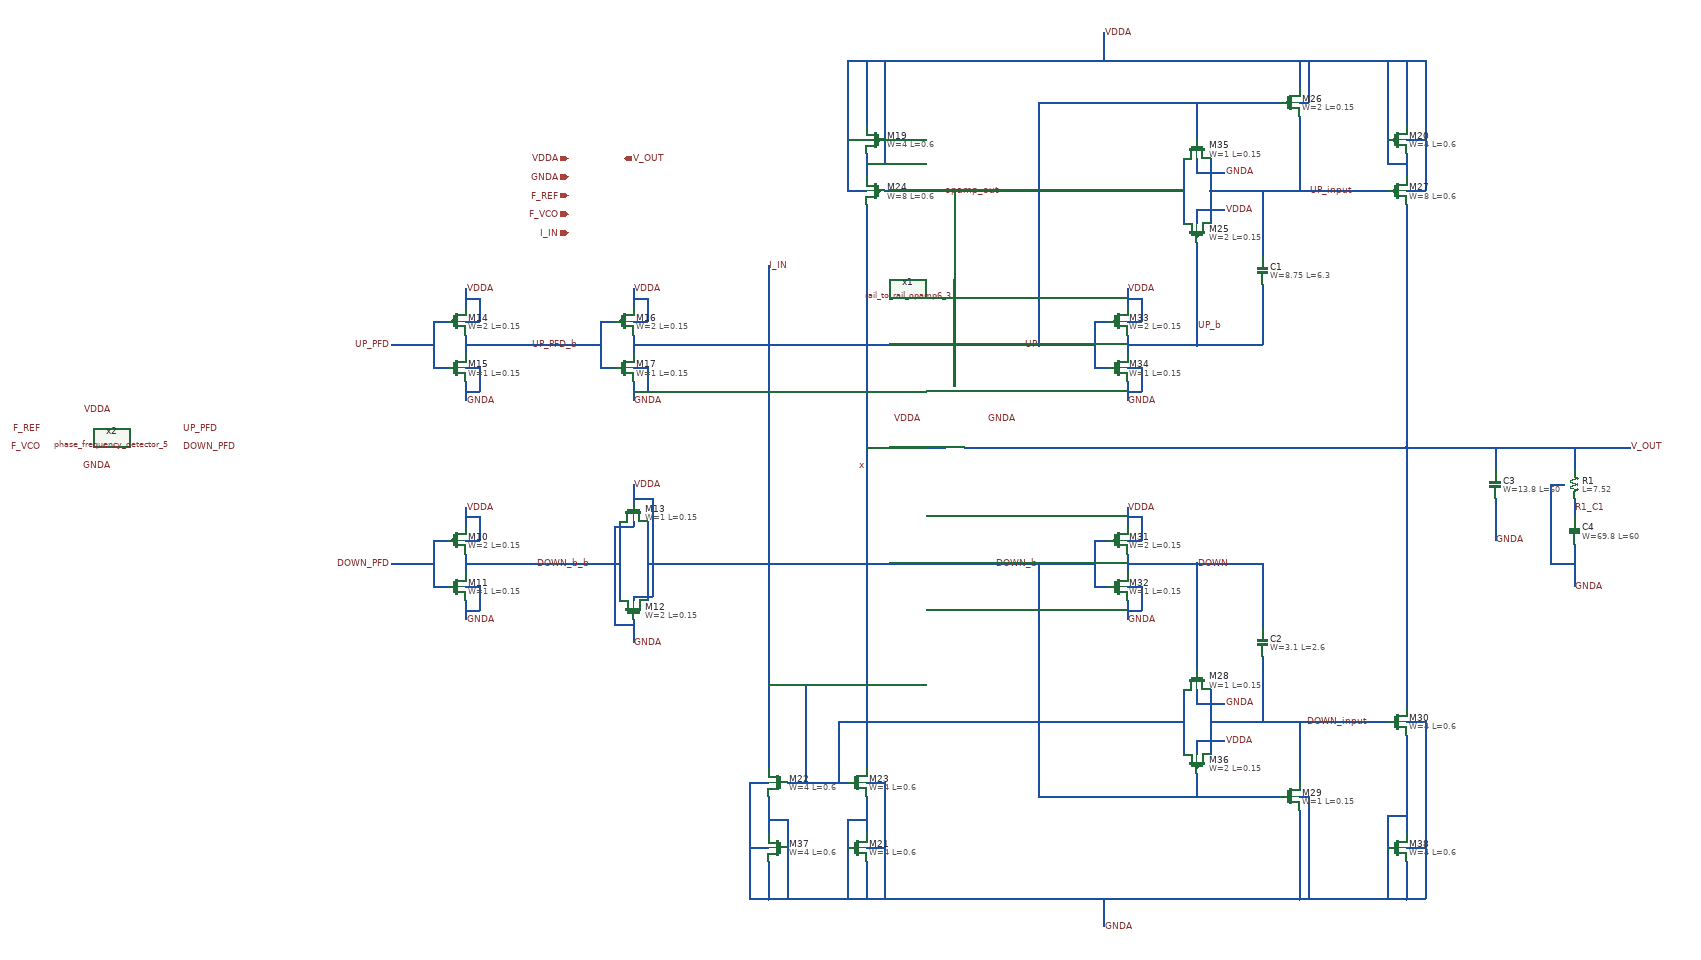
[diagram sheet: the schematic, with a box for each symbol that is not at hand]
v {xschem version=3.4.6 file_version=1.2}
G {}
K {}
V {}
S {}
E {}
N 1110 -1300 1210 -1300 {
lab=UP_PFD_b}
N 1150 -830 1340 -830 {
lab=DOWN_b_b}
N 850 -1300 890 -1300 {
lab=UP_PFD}
N 850 -830 890 -830 {
lab=DOWN_PFD}
N 1340 -920 1340 -750 {
lab=DOWN_b_b}
N 1400 -920 1400 -750 {
lab=DOWN_b}
N 1370 -1000 1370 -960 {
lab=VDDA}
N 1370 -760 1370 -750 {
lab=VDDA}
N 1370 -760 1410 -760 {
lab=VDDA}
N 1410 -970 1410 -760 {
lab=VDDA}
N 1370 -970 1410 -970 {
lab=VDDA}
N 1370 -920 1370 -910 {
lab=GNDA}
N 1330 -910 1370 -910 {
lab=GNDA}
N 1330 -910 1330 -700 {
lab=GNDA}
N 1330 -700 1370 -700 {
lab=GNDA}
N 1370 -710 1370 -660 {
lab=GNDA}
N 1010 -850 1010 -810 {
lab=DOWN_b_b}
N 940 -880 970 -880 {
lab=DOWN_PFD}
N 940 -880 940 -780 {
lab=DOWN_PFD}
N 940 -780 970 -780 {
lab=DOWN_PFD}
N 1010 -830 1150 -830 {
lab=DOWN_b_b}
N 890 -830 940 -830 {
lab=DOWN_PFD}
N 1010 -750 1010 -710 {
lab=GNDA}
N 1010 -950 1010 -910 {
lab=VDDA}
N 1010 -880 1040 -880 {
lab=VDDA}
N 1040 -930 1040 -880 {
lab=VDDA}
N 1010 -930 1040 -930 {
lab=VDDA}
N 1010 -780 1040 -780 {
lab=GNDA}
N 1040 -780 1040 -730 {
lab=GNDA}
N 1010 -730 1040 -730 {
lab=GNDA}
N 1010 -1320 1010 -1280 {
lab=UP_PFD_b}
N 940 -1350 970 -1350 {
lab=UP_PFD}
N 940 -1350 940 -1250 {
lab=UP_PFD}
N 940 -1250 970 -1250 {
lab=UP_PFD}
N 1010 -1300 1110 -1300 {
lab=UP_PFD_b}
N 890 -1300 940 -1300 {
lab=UP_PFD}
N 1010 -1220 1010 -1180 {
lab=GNDA}
N 1010 -1420 1010 -1380 {
lab=VDDA}
N 1010 -1350 1040 -1350 {
lab=VDDA}
N 1040 -1400 1040 -1350 {
lab=VDDA}
N 1010 -1400 1040 -1400 {
lab=VDDA}
N 1010 -1250 1040 -1250 {
lab=GNDA}
N 1040 -1250 1040 -1200 {
lab=GNDA}
N 1010 -1200 1040 -1200 {
lab=GNDA}
N 1370 -1320 1370 -1280 {
lab=UP}
N 1300 -1350 1330 -1350 {
lab=UP_PFD_b}
N 1300 -1350 1300 -1250 {
lab=UP_PFD_b}
N 1300 -1250 1330 -1250 {
lab=UP_PFD_b}
N 1210 -1300 1300 -1300 {
lab=UP_PFD_b}
N 1370 -1220 1370 -1180 {
lab=GNDA}
N 1370 -1420 1370 -1380 {
lab=VDDA}
N 1370 -1350 1400 -1350 {
lab=VDDA}
N 1400 -1400 1400 -1350 {
lab=VDDA}
N 1370 -1400 1400 -1400 {
lab=VDDA}
N 1370 -1250 1400 -1250 {
lab=GNDA}
N 1400 -1250 1400 -1200 {
lab=GNDA}
N 1370 -1200 1400 -1200 {
lab=GNDA}
N 1370 -1300 2240 -1300 {
lab=UP}
N 1700 -360 1830 -360 {
lab=I_IN}
N 1660 -110 2160 -110 {
lab=GNDA}
N 1620 -360 1660 -360 {
lab=GNDA}
N 1620 -360 1620 -110 {
lab=GNDA}
N 1620 -110 1660 -110 {
lab=GNDA}
N 1870 -360 1910 -360 {
lab=GNDA}
N 1830 -1630 1870 -1630 {
lab=VDDA}
N 2160 -110 2200 -110 {
lab=GNDA}
N 1830 -1910 1830 -1630 {
lab=VDDA}
N 2800 -1910 2800 -1850 {
lab=VDDA}
N 2800 -1820 2820 -1820 {
lab=VDDA}
N 2820 -1910 2820 -1820 {
lab=VDDA}
N 3070 -1910 3070 -1630 {
lab=VDDA}
N 2200 -110 2800 -110 {
lab=GNDA}
N 2800 -300 2800 -110 {
lab=GNDA}
N 3030 -490 3070 -490 {
lab=GNDA}
N 3030 -110 3070 -110 {
lab=GNDA}
N 2060 -1630 2060 -1210 {
lab=opamp_out}
N 1740 -570 1740 -360 {
lab=I_IN}
N 1660 -570 1740 -570 {
lab=I_IN}
N 1910 -360 1910 -110 {
lab=GNDA}
N 1810 -490 2550 -490 {
lab=I_IN}
N 2580 -1520 2580 -1300 {
lab=UP_b}
N 2240 -1820 2760 -1820 {
lab=UP}
N 2240 -1820 2240 -1300 {
lab=UP}
N 2800 -1790 2800 -1630 {
lab=UP_input}
N 2610 -1630 2990 -1630 {
lab=UP_input}
N 2520 -830 2580 -830 {
lab=DOWN}
N 2580 -830 2580 -600 {
lab=DOWN}
N 2240 -830 2240 -330 {
lab=DOWN_b}
N 2240 -330 2760 -330 {
lab=DOWN_b}
N 2430 -850 2430 -810 {
lab=DOWN}
N 2360 -880 2390 -880 {
lab=DOWN_b}
N 2360 -880 2360 -780 {
lab=DOWN_b}
N 2360 -780 2390 -780 {
lab=DOWN_b}
N 2430 -750 2430 -710 {
lab=GNDA}
N 2430 -950 2430 -910 {
lab=VDDA}
N 2430 -880 2460 -880 {
lab=VDDA}
N 2460 -930 2460 -880 {
lab=VDDA}
N 2430 -930 2460 -930 {
lab=VDDA}
N 2430 -780 2460 -780 {
lab=GNDA}
N 2460 -780 2460 -730 {
lab=GNDA}
N 2430 -730 2460 -730 {
lab=GNDA}
N 2430 -830 2520 -830 {
lab=DOWN}
N 2430 -1320 2430 -1280 {
lab=UP_b}
N 2360 -1350 2390 -1350 {
lab=UP}
N 2360 -1350 2360 -1250 {
lab=UP}
N 2360 -1250 2390 -1250 {
lab=UP}
N 2240 -1300 2360 -1300 {
lab=UP}
N 2430 -1220 2430 -1180 {
lab=GNDA}
N 2430 -1420 2430 -1380 {
lab=VDDA}
N 2430 -1350 2460 -1350 {
lab=VDDA}
N 2460 -1400 2460 -1350 {
lab=VDDA}
N 2430 -1400 2460 -1400 {
lab=VDDA}
N 2430 -1250 2460 -1250 {
lab=GNDA}
N 2460 -1250 2460 -1200 {
lab=GNDA}
N 2430 -1200 2460 -1200 {
lab=GNDA}
N 2430 -1300 2520 -1300 {
lab=UP_b}
N 2520 -1300 2580 -1300 {
lab=UP_b}
N 1660 -610 1660 -390 {
lab=I_IN}
N 1660 -670 1660 -610 {
lab=I_IN}
N 2610 -1700 2610 -1630 {
lab=UP_input}
N 2550 -1700 2550 -1560 {
lab=opamp_out}
N 2610 -1630 2610 -1560 {
lab=UP_input}
N 1910 -1630 2550 -1630 {
lab=opamp_out}
N 2800 -110 3030 -110 {
lab=GNDA}
N 2610 -560 2610 -420 {
lab=DOWN_input}
N 2550 -560 2550 -420 {
lab=I_IN}
N 2610 -490 2990 -490 {
lab=DOWN_input}
N 3070 -490 3070 -110 {
lab=GNDA}
N 1810 -490 1810 -360 {
lab=I_IN}
N 2800 -490 2800 -360 {
lab=DOWN_input}
N 2800 -330 2820 -330 {
lab=GNDA}
N 2820 -330 2820 -110 {
lab=GNDA}
N 2580 -380 2580 -330 {
lab=DOWN_b}
N 2580 -1820 2580 -1740 {
lab=UP}
N 2580 -1300 2720 -1300 {
lab=UP_b}
N 2720 -1430 2720 -1300 {
lab=UP_b}
N 2720 -1630 2720 -1490 {
lab=UP_input}
N 2720 -830 2720 -690 {
lab=DOWN}
N 2720 -630 2720 -490 {
lab=DOWN_input}
N 2580 -830 2720 -830 {
lab=DOWN}
N 3030 -1080 3110 -1080 {
lab=V_OUT}
N 1400 -830 2240 -830 {
lab=DOWN_b}
N 2240 -830 2360 -830 {
lab=DOWN_b}
N 2380 -1970 2380 -1910 {
lab=VDDA}
N 2380 -110 2380 -50 {
lab=GNDA}
N 2580 -450 2640 -450 {
lab=VDDA}
N 2580 -450 2580 -420 {
lab=VDDA}
N 2580 -560 2580 -530 {
lab=GNDA}
N 2580 -530 2640 -530 {
lab=GNDA}
N 2580 -1590 2640 -1590 {
lab=VDDA}
N 2580 -1590 2580 -1560 {
lab=VDDA}
N 2580 -1700 2580 -1670 {
lab=GNDA}
N 2580 -1670 2640 -1670 {
lab=GNDA}
N 1660 -1470 1660 -670 {lab=I_IN}
N 1870 -1600 1870 -390 {lab=x}
N 3030 -1600 3030 -1080 {lab=V_OUT}
N 3030 -1080 3030 -520 {lab=V_OUT}
N 1870 -1080 2040 -1080 {lab=x}
N 2080 -1080 3030 -1080 {lab=V_OUT}
N 1830 -1740 1870 -1740 {
lab=VDDA}
N 1870 -1710 1870 -1660 {lab=VDDA}
N 1870 -1910 1870 -1770 {lab=VDDA}
N 3030 -1710 3030 -1660 {lab=VDDA}
N 3030 -1910 3030 -1770 {lab=VDDA}
N 2990 -1910 2990 -1740 {lab=VDDA}
N 1910 -1910 1910 -1740 {lab=VDDA}
N 1870 -1690 1910 -1690 {lab=VDDA}
N 1910 -1740 1910 -1690 {lab=VDDA}
N 3030 -1740 3070 -1740 {lab=VDDA}
N 2990 -1690 3030 -1690 {lab=VDDA}
N 2990 -1740 2990 -1690 {lab=VDDA}
N 3030 -1630 3070 -1630 {lab=VDDA}
N 1660 -330 1660 -250 {
lab=GNDA}
N 1870 -330 1870 -250 {
lab=GNDA}
N 3030 -460 3030 -250 {
lab=GNDA}
N 1620 -220 1660 -220 {
lab=GNDA}
N 1870 -220 1910 -220 {
lab=GNDA}
N 1660 -190 1660 -110 {lab=GNDA}
N 1870 -190 1870 -110 {lab=GNDA}
N 1830 -220 1830 -110 {lab=GNDA}
N 1700 -220 1700 -110 {lab=GNDA}
N 1660 -280 1700 -280 {lab=GNDA}
N 1700 -280 1700 -220 {lab=GNDA}
N 1830 -280 1830 -220 {lab=GNDA}
N 1830 -280 1870 -280 {lab=GNDA}
N 3030 -190 3030 -110 {lab=GNDA}
N 2990 -220 2990 -110 {lab=GNDA}
N 2990 -290 2990 -220 {lab=GNDA}
N 2990 -290 3030 -290 {lab=GNDA}
N 3030 -220 3070 -220 {lab=GNDA}
N 1830 -1910 3070 -1910 {lab=VDDA}
N 3390 -970 3390 -920 {
lab=R1_C1}
N 3340 -1000 3370 -1000 {
lab=GNDA}
N 3340 -1000 3340 -830 {
lab=GNDA}
N 3340 -830 3390 -830 {
lab=GNDA}
N 3390 -870 3390 -780 {lab=GNDA}
N 3110 -1080 3510 -1080 {lab=V_OUT}
N 3220 -1080 3220 -1030 {lab=V_OUT}
N 3390 -1080 3390 -1030 {lab=V_OUT}
N 3220 -970 3220 -880 {lab=GNDA}
C {devices/lab_wire.sym} 1150 -1300 0 1 {name=p15 sig_type=std_logic lab=UP_PFD_b}
C {devices/lab_wire.sym} 850 -1300 0 0 {name=p2 sig_type=std_logic lab=UP_PFD}
C {devices/lab_wire.sym} 850 -830 2 1 {name=p7 sig_type=std_logic lab=DOWN_PFD}
C {sky130_fd_pr/pfet_01v8.sym} 1370 -730 3 0 {name=M12
L=0.15
W=2
nf=2
mult=1
ad="'int((nf+1)/2) * W/nf * 0.29'" 
pd="'2*int((nf+1)/2) * (W/nf + 0.29)'"
as="'int((nf+2)/2) * W/nf * 0.29'" 
ps="'2*int((nf+2)/2) * (W/nf + 0.29)'"
nrd="'0.29 / W'" nrs="'0.29 / W'"
sa=0 sb=0 sd=0
model=pfet_01v8
spiceprefix=X
}
C {sky130_fd_pr/nfet_01v8.sym} 1370 -940 1 0 {name=M13
L=0.15
W=1
nf=1 
mult=1
ad="'int((nf+1)/2) * W/nf * 0.29'" 
pd="'2*int((nf+1)/2) * (W/nf + 0.29)'"
as="'int((nf+2)/2) * W/nf * 0.29'" 
ps="'2*int((nf+2)/2) * (W/nf + 0.29)'"
nrd="'0.29 / W'" nrs="'0.29 / W'"
sa=0 sb=0 sd=0
model=nfet_01v8
spiceprefix=X
}
C {sky130_fd_pr/pfet_01v8.sym} 990 -880 0 0 {name=M10
L=0.15
W=2
nf=2
mult=1
ad="'int((nf+1)/2) * W/nf * 0.29'" 
pd="'2*int((nf+1)/2) * (W/nf + 0.29)'"
as="'int((nf+2)/2) * W/nf * 0.29'" 
ps="'2*int((nf+2)/2) * (W/nf + 0.29)'"
nrd="'0.29 / W'" nrs="'0.29 / W'"
sa=0 sb=0 sd=0
model=pfet_01v8
spiceprefix=X
}
C {sky130_fd_pr/nfet_01v8.sym} 990 -780 2 1 {name=M11
L=0.15
W=1
nf=1 
mult=1
ad="'int((nf+1)/2) * W/nf * 0.29'" 
pd="'2*int((nf+1)/2) * (W/nf + 0.29)'"
as="'int((nf+2)/2) * W/nf * 0.29'" 
ps="'2*int((nf+2)/2) * (W/nf + 0.29)'"
nrd="'0.29 / W'" nrs="'0.29 / W'"
sa=0 sb=0 sd=0
model=nfet_01v8
spiceprefix=X
}
C {sky130_fd_pr/pfet_01v8.sym} 990 -1350 0 0 {name=M14
L=0.15
W=2
nf=2
mult=1
ad="'int((nf+1)/2) * W/nf * 0.29'" 
pd="'2*int((nf+1)/2) * (W/nf + 0.29)'"
as="'int((nf+2)/2) * W/nf * 0.29'" 
ps="'2*int((nf+2)/2) * (W/nf + 0.29)'"
nrd="'0.29 / W'" nrs="'0.29 / W'"
sa=0 sb=0 sd=0
model=pfet_01v8
spiceprefix=X
}
C {sky130_fd_pr/nfet_01v8.sym} 990 -1250 2 1 {name=M15
L=0.15
W=1
nf=1 
mult=1
ad="'int((nf+1)/2) * W/nf * 0.29'" 
pd="'2*int((nf+1)/2) * (W/nf + 0.29)'"
as="'int((nf+2)/2) * W/nf * 0.29'" 
ps="'2*int((nf+2)/2) * (W/nf + 0.29)'"
nrd="'0.29 / W'" nrs="'0.29 / W'"
sa=0 sb=0 sd=0
model=nfet_01v8
spiceprefix=X
}
C {sky130_fd_pr/pfet_01v8.sym} 1350 -1350 0 0 {name=M16
L=0.15
W=2
nf=2
mult=1
ad="'int((nf+1)/2) * W/nf * 0.29'" 
pd="'2*int((nf+1)/2) * (W/nf + 0.29)'"
as="'int((nf+2)/2) * W/nf * 0.29'" 
ps="'2*int((nf+2)/2) * (W/nf + 0.29)'"
nrd="'0.29 / W'" nrs="'0.29 / W'"
sa=0 sb=0 sd=0
model=pfet_01v8
spiceprefix=X
}
C {sky130_fd_pr/nfet_01v8.sym} 1350 -1250 2 1 {name=M17
L=0.15
W=1
nf=1 
mult=1
ad="'int((nf+1)/2) * W/nf * 0.29'" 
pd="'2*int((nf+1)/2) * (W/nf + 0.29)'"
as="'int((nf+2)/2) * W/nf * 0.29'" 
ps="'2*int((nf+2)/2) * (W/nf + 0.29)'"
nrd="'0.29 / W'" nrs="'0.29 / W'"
sa=0 sb=0 sd=0
model=nfet_01v8
spiceprefix=X
}
C {devices/ipin.sym} 1230 -1700 0 0 {name=p3 lab=VDDA}
C {devices/opin.sym} 1350 -1700 0 0 {name=p11 lab=V_OUT}
C {devices/lab_pin.sym} 1010 -710 0 1 {name=p27 sig_type=std_logic lab=GNDA}
C {devices/lab_pin.sym} 1010 -950 0 1 {name=p28 sig_type=std_logic lab=VDDA}
C {devices/lab_pin.sym} 1370 -660 0 1 {name=p29 sig_type=std_logic lab=GNDA}
C {devices/lab_pin.sym} 1370 -1000 0 1 {name=p30 sig_type=std_logic lab=VDDA}
C {devices/lab_pin.sym} 1010 -1180 0 1 {name=p31 sig_type=std_logic lab=GNDA}
C {devices/lab_pin.sym} 1010 -1420 0 1 {name=p32 sig_type=std_logic lab=VDDA}
C {devices/lab_pin.sym} 1370 -1180 0 1 {name=p33 sig_type=std_logic lab=GNDA}
C {devices/lab_pin.sym} 1370 -1420 0 1 {name=p34 sig_type=std_logic lab=VDDA}
C {devices/ipin.sym} 1230 -1660 0 0 {name=p35 lab=GNDA}
C {devices/ipin.sym} 1230 -1620 0 0 {name=p36 lab=F_REF}
C {devices/ipin.sym} 1230 -1580 0 0 {name=p37 lab=F_VCO}
C {devices/ipin.sym} 1230 -1540 0 0 {name=p38 lab=I_IN}
C {sky130_fd_pr/nfet_01v8.sym} 1680 -360 0 1 {name=M22
L=0.6
W=4
nf=2 
mult=1
ad="'int((nf+1)/2) * W/nf * 0.29'" 
pd="'2*int((nf+1)/2) * (W/nf + 0.29)'"
as="'int((nf+2)/2) * W/nf * 0.29'" 
ps="'2*int((nf+2)/2) * (W/nf + 0.29)'"
nrd="'0.29 / W'" nrs="'0.29 / W'"
sa=0 sb=0 sd=0
model=nfet_01v8
spiceprefix=X
}
C {sky130_fd_pr/nfet_01v8.sym} 1850 -360 0 0 {name=M23
L=0.6
W=4
nf=2 
mult=1
ad="'int((nf+1)/2) * W/nf * 0.29'" 
pd="'2*int((nf+1)/2) * (W/nf + 0.29)'"
as="'int((nf+2)/2) * W/nf * 0.29'" 
ps="'2*int((nf+2)/2) * (W/nf + 0.29)'"
nrd="'0.29 / W'" nrs="'0.29 / W'"
sa=0 sb=0 sd=0
model=nfet_01v8
spiceprefix=X
}
C {sky130_fd_pr/pfet_01v8.sym} 1890 -1630 2 0 {name=M24
L=0.6
W=8
nf=4
mult=1
ad="'int((nf+1)/2) * W/nf * 0.29'" 
pd="'2*int((nf+1)/2) * (W/nf + 0.29)'"
as="'int((nf+2)/2) * W/nf * 0.29'" 
ps="'2*int((nf+2)/2) * (W/nf + 0.29)'"
nrd="'0.29 / W'" nrs="'0.29 / W'"
sa=0 sb=0 sd=0
model=pfet_01v8
spiceprefix=X
}
C {devices/lab_wire.sym} 1870 -1040 0 0 {name=p9 sig_type=std_logic lab=x}
C {sky130_fd_pr/pfet_01v8.sym} 2580 -1540 3 0 {name=M25
L=0.15
W=2
nf=2
mult=1
ad="'int((nf+1)/2) * W/nf * 0.29'" 
pd="'2*int((nf+1)/2) * (W/nf + 0.29)'"
as="'int((nf+2)/2) * W/nf * 0.29'" 
ps="'2*int((nf+2)/2) * (W/nf + 0.29)'"
nrd="'0.29 / W'" nrs="'0.29 / W'"
sa=0 sb=0 sd=0
model=pfet_01v8
spiceprefix=X
}
C {sky130_fd_pr/pfet_01v8.sym} 2780 -1820 0 0 {name=M26
L=0.15
W=2
nf=2
mult=1
ad="'int((nf+1)/2) * W/nf * 0.29'" 
pd="'2*int((nf+1)/2) * (W/nf + 0.29)'"
as="'int((nf+2)/2) * W/nf * 0.29'" 
ps="'2*int((nf+2)/2) * (W/nf + 0.29)'"
nrd="'0.29 / W'" nrs="'0.29 / W'"
sa=0 sb=0 sd=0
model=pfet_01v8
spiceprefix=X
}
C {sky130_fd_pr/pfet_01v8.sym} 3010 -1630 0 0 {name=M27
L=0.6
W=8
nf=4
mult=1
ad="'int((nf+1)/2) * W/nf * 0.29'" 
pd="'2*int((nf+1)/2) * (W/nf + 0.29)'"
as="'int((nf+2)/2) * W/nf * 0.29'" 
ps="'2*int((nf+2)/2) * (W/nf + 0.29)'"
nrd="'0.29 / W'" nrs="'0.29 / W'"
sa=0 sb=0 sd=0
model=pfet_01v8
spiceprefix=X
}
C {devices/lab_wire.sym} 2240 -1300 2 1 {name=p19 sig_type=std_logic lab=UP}
C {devices/lab_wire.sym} 2580 -1340 0 1 {name=p39 sig_type=std_logic lab=UP_b}
C {sky130_fd_pr/nfet_01v8.sym} 2580 -580 1 0 {name=M28
L=0.15
W=1
nf=1 
mult=1
ad="'int((nf+1)/2) * W/nf * 0.29'" 
pd="'2*int((nf+1)/2) * (W/nf + 0.29)'"
as="'int((nf+2)/2) * W/nf * 0.29'" 
ps="'2*int((nf+2)/2) * (W/nf + 0.29)'"
nrd="'0.29 / W'" nrs="'0.29 / W'"
sa=0 sb=0 sd=0
model=nfet_01v8
spiceprefix=X
}
C {sky130_fd_pr/nfet_01v8.sym} 2780 -330 0 0 {name=M29
L=0.15
W=1
nf=1 
mult=1
ad="'int((nf+1)/2) * W/nf * 0.29'" 
pd="'2*int((nf+1)/2) * (W/nf + 0.29)'"
as="'int((nf+2)/2) * W/nf * 0.29'" 
ps="'2*int((nf+2)/2) * (W/nf + 0.29)'"
nrd="'0.29 / W'" nrs="'0.29 / W'"
sa=0 sb=0 sd=0
model=nfet_01v8
spiceprefix=X
}
C {devices/lab_wire.sym} 2240 -830 0 0 {name=p40 sig_type=std_logic lab=DOWN_b}
C {sky130_fd_pr/nfet_01v8.sym} 3010 -490 0 0 {name=M30
L=0.6
W=4
nf=2 
mult=1
ad="'int((nf+1)/2) * W/nf * 0.29'" 
pd="'2*int((nf+1)/2) * (W/nf + 0.29)'"
as="'int((nf+2)/2) * W/nf * 0.29'" 
ps="'2*int((nf+2)/2) * (W/nf + 0.29)'"
nrd="'0.29 / W'" nrs="'0.29 / W'"
sa=0 sb=0 sd=0
model=nfet_01v8
spiceprefix=X
}
C {devices/lab_wire.sym} 2820 -1630 2 0 {name=p41 sig_type=std_logic lab=UP_input}
C {devices/lab_wire.sym} 2950 -490 0 0 {name=p42 sig_type=std_logic lab=DOWN_input}
C {devices/lab_wire.sym} 2160 -1630 0 0 {name=p43 sig_type=std_logic lab=opamp_out}
C {sky130_fd_pr/pfet_01v8.sym} 2410 -880 0 0 {name=M31
L=0.15
W=2
nf=2
mult=1
ad="'int((nf+1)/2) * W/nf * 0.29'" 
pd="'2*int((nf+1)/2) * (W/nf + 0.29)'"
as="'int((nf+2)/2) * W/nf * 0.29'" 
ps="'2*int((nf+2)/2) * (W/nf + 0.29)'"
nrd="'0.29 / W'" nrs="'0.29 / W'"
sa=0 sb=0 sd=0
model=pfet_01v8
spiceprefix=X
}
C {sky130_fd_pr/nfet_01v8.sym} 2410 -780 2 1 {name=M32
L=0.15
W=1
nf=1 
mult=1
ad="'int((nf+1)/2) * W/nf * 0.29'" 
pd="'2*int((nf+1)/2) * (W/nf + 0.29)'"
as="'int((nf+2)/2) * W/nf * 0.29'" 
ps="'2*int((nf+2)/2) * (W/nf + 0.29)'"
nrd="'0.29 / W'" nrs="'0.29 / W'"
sa=0 sb=0 sd=0
model=nfet_01v8
spiceprefix=X
}
C {sky130_fd_pr/pfet_01v8.sym} 2410 -1350 0 0 {name=M33
L=0.15
W=2
nf=2
mult=1
ad="'int((nf+1)/2) * W/nf * 0.29'" 
pd="'2*int((nf+1)/2) * (W/nf + 0.29)'"
as="'int((nf+2)/2) * W/nf * 0.29'" 
ps="'2*int((nf+2)/2) * (W/nf + 0.29)'"
nrd="'0.29 / W'" nrs="'0.29 / W'"
sa=0 sb=0 sd=0
model=pfet_01v8
spiceprefix=X
}
C {sky130_fd_pr/nfet_01v8.sym} 2410 -1250 2 1 {name=M34
L=0.15
W=1
nf=1 
mult=1
ad="'int((nf+1)/2) * W/nf * 0.29'" 
pd="'2*int((nf+1)/2) * (W/nf + 0.29)'"
as="'int((nf+2)/2) * W/nf * 0.29'" 
ps="'2*int((nf+2)/2) * (W/nf + 0.29)'"
nrd="'0.29 / W'" nrs="'0.29 / W'"
sa=0 sb=0 sd=0
model=nfet_01v8
spiceprefix=X
}
C {devices/lab_wire.sym} 1660 -1470 0 1 {name=p44 sig_type=std_logic lab=I_IN}
C {devices/lab_wire.sym} 2580 -830 0 1 {name=p45 sig_type=std_logic lab=DOWN}
C {sky130_fd_pr/nfet_01v8.sym} 2580 -1720 1 0 {name=M35
L=0.15
W=1
nf=1 
mult=1
ad="'int((nf+1)/2) * W/nf * 0.29'" 
pd="'2*int((nf+1)/2) * (W/nf + 0.29)'"
as="'int((nf+2)/2) * W/nf * 0.29'" 
ps="'2*int((nf+2)/2) * (W/nf + 0.29)'"
nrd="'0.29 / W'" nrs="'0.29 / W'"
sa=0 sb=0 sd=0
model=nfet_01v8
spiceprefix=X
}
C {sky130_fd_pr/pfet_01v8.sym} 2580 -400 3 0 {name=M36
L=0.15
W=2
nf=2
mult=1
ad="'int((nf+1)/2) * W/nf * 0.29'" 
pd="'2*int((nf+1)/2) * (W/nf + 0.29)'"
as="'int((nf+2)/2) * W/nf * 0.29'" 
ps="'2*int((nf+2)/2) * (W/nf + 0.29)'"
nrd="'0.29 / W'" nrs="'0.29 / W'"
sa=0 sb=0 sd=0
model=pfet_01v8
spiceprefix=X
}
C {sky130_fd_pr/cap_mim_m3_1.sym} 2720 -1460 0 0 {name=C1 model=cap_mim_m3_1 W=8.75 L=6.3 MF=1 spiceprefix=X}
C {sky130_fd_pr/cap_mim_m3_1.sym} 2720 -660 2 0 {name=C2 model=cap_mim_m3_1 W=3.1 L=2.6 MF=1 spiceprefix=X}
C {devices/lab_pin.sym} 2380 -1970 0 1 {name=p26 sig_type=std_logic lab=VDDA}
C {devices/lab_pin.sym} 2380 -50 0 1 {name=p18 sig_type=std_logic lab=GNDA}
C {devices/lab_pin.sym} 2430 -1420 0 1 {name=p5 sig_type=std_logic lab=VDDA}
C {devices/lab_pin.sym} 2430 -1180 0 1 {name=p6 sig_type=std_logic lab=GNDA}
C {devices/lab_pin.sym} 2430 -950 0 1 {name=p8 sig_type=std_logic lab=VDDA}
C {devices/lab_pin.sym} 2430 -710 0 1 {name=p10 sig_type=std_logic lab=GNDA}
C {devices/lab_pin.sym} 2640 -450 0 1 {name=p13 sig_type=std_logic lab=VDDA}
C {devices/lab_pin.sym} 2640 -530 0 1 {name=p14 sig_type=std_logic lab=GNDA}
C {devices/lab_pin.sym} 2640 -1590 0 1 {name=p16 sig_type=std_logic lab=VDDA}
C {devices/lab_pin.sym} 2640 -1670 0 1 {name=p17 sig_type=std_logic lab=GNDA}
C {devices/lab_wire.sym} 1160 -830 2 0 {name=p1 sig_type=std_logic lab=DOWN_b_b}
C {devices/lab_pin.sym} 1990 -1140 0 0 {name=p4 sig_type=std_logic lab=VDDA}
C {devices/lab_pin.sym} 2130 -1140 0 1 {name=p20 sig_type=std_logic lab=GNDA}
C {devices/lab_pin.sym} 250 -1160 0 0 {name=p21 sig_type=std_logic lab=VDDA}
C {devices/lab_pin.sym} 250 -1040 0 0 {name=p22 sig_type=std_logic lab=GNDA}
C {devices/lab_wire.sym} 400 -1120 0 1 {name=p23 sig_type=std_logic lab=UP_PFD}
C {devices/lab_wire.sym} 400 -1080 2 0 {name=p24 sig_type=std_logic lab=DOWN_PFD}
C {devices/lab_wire.sym} 100 -1120 0 0 {name=p25 sig_type=std_logic lab=F_REF}
C {devices/lab_wire.sym} 100 -1080 2 1 {name=p46 sig_type=std_logic lab=F_VCO}
C {/foss/designs/my_design/projects/pll/pfd/xschem_ngspice/phase_frequency_detector_5.sym} 250 -1100 0 0 {name=x2}
C {sky130_fd_pr/pfet_01v8.sym} 1890 -1740 0 1 {name=M19
L=0.6
W=4
nf=2
mult=1
ad="'int((nf+1)/2) * W/nf * 0.29'" 
pd="'2*int((nf+1)/2) * (W/nf + 0.29)'"
as="'int((nf+2)/2) * W/nf * 0.29'" 
ps="'2*int((nf+2)/2) * (W/nf + 0.29)'"
nrd="'0.29 / W'" nrs="'0.29 / W'"
sa=0 sb=0 sd=0
model=pfet_01v8
spiceprefix=X
}
C {sky130_fd_pr/pfet_01v8.sym} 3010 -1740 0 0 {name=M20
L=0.6
W=4
nf=2
mult=1
ad="'int((nf+1)/2) * W/nf * 0.29'" 
pd="'2*int((nf+1)/2) * (W/nf + 0.29)'"
as="'int((nf+2)/2) * W/nf * 0.29'" 
ps="'2*int((nf+2)/2) * (W/nf + 0.29)'"
nrd="'0.29 / W'" nrs="'0.29 / W'"
sa=0 sb=0 sd=0
model=pfet_01v8
spiceprefix=X
}
C {sky130_fd_pr/nfet_01v8.sym} 1850 -220 0 0 {name=M21
L=0.6
W=4
nf=2 
mult=1
ad="'int((nf+1)/2) * W/nf * 0.29'" 
pd="'2*int((nf+1)/2) * (W/nf + 0.29)'"
as="'int((nf+2)/2) * W/nf * 0.29'" 
ps="'2*int((nf+2)/2) * (W/nf + 0.29)'"
nrd="'0.29 / W'" nrs="'0.29 / W'"
sa=0 sb=0 sd=0
model=nfet_01v8
spiceprefix=X
}
C {sky130_fd_pr/nfet_01v8.sym} 1680 -220 0 1 {name=M37
L=0.6
W=4
nf=2 
mult=1
ad="'int((nf+1)/2) * W/nf * 0.29'" 
pd="'2*int((nf+1)/2) * (W/nf + 0.29)'"
as="'int((nf+2)/2) * W/nf * 0.29'" 
ps="'2*int((nf+2)/2) * (W/nf + 0.29)'"
nrd="'0.29 / W'" nrs="'0.29 / W'"
sa=0 sb=0 sd=0
model=nfet_01v8
spiceprefix=X
}
C {sky130_fd_pr/nfet_01v8.sym} 3010 -220 0 0 {name=M38
L=0.6
W=4
nf=2 
mult=1
ad="'int((nf+1)/2) * W/nf * 0.29'" 
pd="'2*int((nf+1)/2) * (W/nf + 0.29)'"
as="'int((nf+2)/2) * W/nf * 0.29'" 
ps="'2*int((nf+2)/2) * (W/nf + 0.29)'"
nrd="'0.29 / W'" nrs="'0.29 / W'"
sa=0 sb=0 sd=0
model=nfet_01v8
spiceprefix=X
}
C {/foss/designs/my_design/projects/pll/charge_pump/xschem_ngspice/rail_to_rail_opamp6_3.sym} 2060 -1140 3 0 {name=x1}
C {devices/lab_pin.sym} 3510 -1080 0 1 {name=p47 sig_type=std_logic lab=V_OUT}
C {devices/lab_pin.sym} 3390 -780 0 1 {name=p49 sig_type=std_logic lab=GNDA}
C {sky130_fd_pr/cap_mim_m3_1.sym} 3220 -1000 2 0 {name=C3 model=cap_mim_m3_1 W=13.8 L=60 MF=1 spiceprefix=X}
C {sky130_fd_pr/cap_mim_m3_1.sym} 3390 -900 2 0 {name=C4 model=cap_mim_m3_1 W=69.8 L=60 MF=1 spiceprefix=X}
C {sky130_fd_pr/res_xhigh_po_0p35.sym} 3390 -1000 0 0 {name=R1
L=7.52
model=res_xhigh_po_0p35
spiceprefix=X
mult=1}
C {devices/lab_pin.sym} 3220 -880 0 1 {name=p51 sig_type=std_logic lab=GNDA}
C {devices/lab_pin.sym} 3390 -950 0 1 {name=p52 sig_type=std_logic lab=R1_C1}
